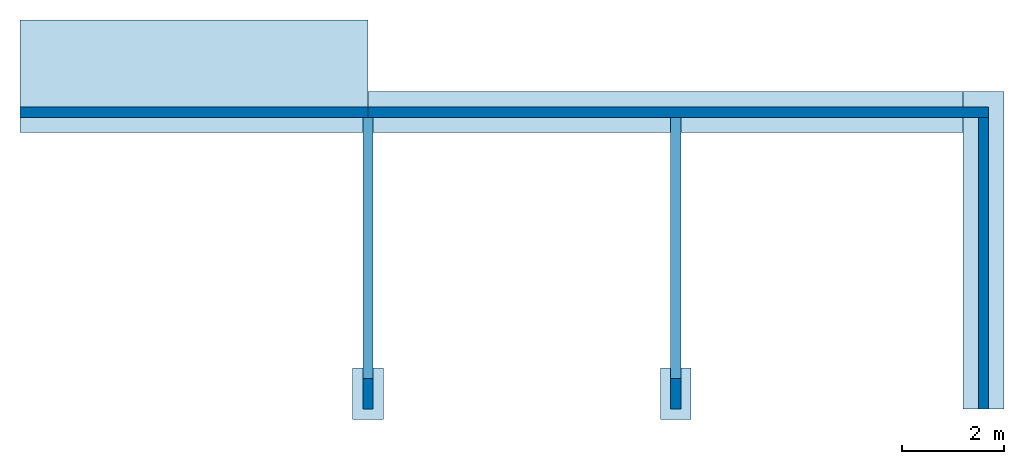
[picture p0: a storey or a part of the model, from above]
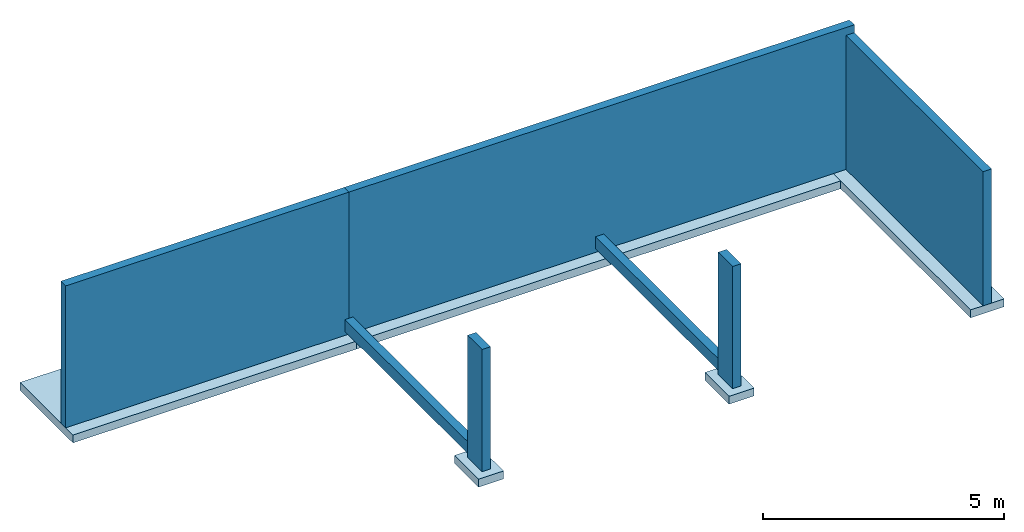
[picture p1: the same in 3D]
Properties of the parts of a building model (IFC2X3)

# File
Description: ViewDefinition [CoordinationView]
File name: Numéro du projet
Time: 2015-11-24T11:05:04
Written by: The EXPRESS Data Manager Version 5.02.0100.07 : 28 Aug 2013
Made in: 20140606_1530(x64) - Exporter 2015.0.2014.0606 - Default UI
Comment: STEP Physical File produced by: The EXPRESS Data Manager Version 5.02.0100.07 : 28 Aug 2013 * Module: EDMstepFileFactory/EDMstandAlone * Creation date: Tue Nov 24 11:05:04 2015 * Host: NI * Database: C:\Users\nicolas\AppData\Local\Temp\{986D8185-EDF2-4D71-8F7C-B6AD133C0408}\ifc * Database version: 5507 * Database creation date: Tue Nov 24 11:04:53 2015 * Schema: IFC2X3 * Model: DataRepository.ifc * Model creation date: Tue Nov 24 11:04:53 2015 * Header model: DataRepository.ifc_HeaderModel * Header model creation date: Tue Nov 24 11:04:53 2015 * EDMuser: sdai-user * EDMgroup: sdai-group * License ID and type: 5605 : Permanent license. Expiry date: * EDMstepFileFactory options: 020000

# IfcProject, Numéro du projet
LongName: Nom du projet; Phase: Etat du projet

# IfcSite, Default
RefLatitude: 48, 51, 23, 999633; RefLongitude: 2, 21, 3, 553905; RefElevation: 0 m
Autre - Adresse du projet: Entrer l'adresse ici; Catégorie: Informations sur le projet; Date de fin du projet: Date de fin; Etat du projet: Etat du projet; Nom du client: Propriétaire; Nom du projet: Nom du projet; Numéro de projet: Numéro du projet

# IfcBuilding
Pset_BuildingCommon - NumberOfStoreys: 3
Autre - Catégorie: Informations sur le projet; Adresse du projet: Entrer l'adresse ici; Date de fin du projet: Date de fin; Etat du projet: Etat du projet; Nom du client: Propriétaire; Nom du projet: Nom du projet; Numéro de projet: Numéro du projet

# IfcBuildingStorey (3)
Autre - Catégorie: Niveaux; Famille: Niveau: Ligne du Niveau; Famille et type: Niveau: Ligne du Niveau; ID du type: Niveau: Ligne du Niveau; Type: Niveau: Ligne du Niveau; Nom de la famille: Niveau
Cotes - Hauteur de calcul: 0 m
Données d'identification - Etage de bâtiment: yes; Structure: no; Nom du type: Ligne du Niveau
Contraintes - Base de l'élévation: Point de base du projet
Graphismes - Couleur: 12632256; Epaisseur des lignes: 1; Motif des lignes: Tiret point; Symbole: Marqueur de niveau - Point triangulaire: Marqueur de niveau - Point triangulaire; Valeur par défaut du symbole à l'extrémité 1: no; Valeur par défaut du symbole à l'extrémité 2: yes
Name | LongName = Nom | Elevation (m) = Elévation (m)
4 - Fondations | 4 - Fondations | -0.6
3 - Sous sol | 3 - Sous sol | 0
2 - RdC | 2 - RdC | 3

# IfcFooting: Base rectangulaire:100 x 60 x 25 (2)
In: 4 - Fondations
Material: Béton - Béton coulé sur place
Autre - Catégorie: Fondations; Famille: Base rectangulaire: 100 x 60 x 25; Famille et type: Base rectangulaire: 100 x 60 x 25; ID du type: Base rectangulaire: 100 x 60 x 25; Type: Base rectangulaire: 100 x 60 x 25; Nom de la famille: Base rectangulaire
Contraintes - Décalage: 0 m; Hôte: Niveau : 4 - Fondations; Niveau: Niveau: 4 - Fondations; Se déplace avec les quadrillages: yes
Cotes - Elévation à la base: -0.8 m; Elévation en haut: -0.6 m; Largeur: 0.6 m; Longueur: 1 m; Surface: 1.84 m2; Volume: 0.24 m3; Epaisseur: 0.2 m
Matériaux et finitions - Matériau structurel: Béton - Béton coulé sur place
Phase de construction - Phase de création: Nouvelle construction
Structure - Activer le modèle analytique: yes; Enrobage d'armature - Autres faces: Paramètres de l'enrobage d'armature: Enrobage d'armature 1; Enrobage d'armature - Face inférieure: Paramètres de l'enrobage d'armature: Enrobage d'armature 1; Enrobage d'armature - Face supérieure: Paramètres de l'enrobage d'armature: Enrobage d'armature 1
Données d'identification - Nom du type: 100 x 60 x 25
Name (Base rectangulaire:100 x 60 x 25:...)
241491
241772

# IfcFooting: Semelle filante:0.6 x 0.2 (2)
In: 4 - Fondations
PredefinedType: STRIP_FOOTING; Material: Maçonnerie - Béton
Autre - Catégorie: Fondations; Famille: Semelle filante: 0.6 x 0.2; Famille et type: Semelle filante: 0.6 x 0.2; ID du type: Semelle filante: 0.6 x 0.2; Type: Semelle filante: 0.6 x 0.2; Nom de la famille: Semelle filante
Cotes - Elévation à la base: -0.8 m; Elévation en haut: -0.6 m; Largeur: 0.8 m; Epaisseur de fondation: 0.2 m; Largeur côté extérieur: 0.3 m; Largeur côté intérieur: 0.3 m; Longueur de l'extension de fin par défaut: 0 m; Ne pas couper aux insertions: no
Phase de construction - Phase de création: Nouvelle construction
Structure - Activer le modèle analytique: yes; Enrobage d'armature - Autres faces: Paramètres de l'enrobage d'armature: Enrobage d'armature 1; Enrobage d'armature - Face inférieure: Paramètres de l'enrobage d'armature: Enrobage d'armature 1; Enrobage d'armature - Face supérieure: Paramètres de l'enrobage d'armature: Enrobage d'armature 1; Utilisation structurelle: Soutènement
Données d'identification - Nom du type: 0.6 x 0.2
Matériaux et finitions - Matériau structurel: Maçonnerie - Béton
Name (Semelle filante:0.6 x 0.2:...) | Longueur (m) | Volume (m3)
242070 | 5.7 | 0.992
247916 | 12.12 | 1.8592

# IfcFooting: Semelle filante:cantil 2 x 0.2, Semelle filante:cantil 2 x 0.2:242081
In: 4 - Fondations
PredefinedType: STRIP_FOOTING; Material: Maçonnerie - Béton
Autre - Catégorie: Fondations; Famille: Semelle filante: cantil 2 x 0.2; Famille et type: Semelle filante: cantil 2 x 0.2; ID du type: Semelle filante: cantil 2 x 0.2; Type: Semelle filante: cantil 2 x 0.2; Nom de la famille: Semelle filante
Cotes - Elévation à la base: -0.8 m; Elévation en haut: -0.6 m; Largeur: 2.2 m; Longueur: 6.79606 m; Volume: 2.99027 m3; Longueur de l'extension de fin par défaut: 0 m; Ne pas couper aux insertions: no; Epaisseur de fondation: 0.2 m; Largeur côté extérieur: 1.7 m; Largeur côté intérieur: 0.3 m
Phase de construction - Phase de création: Nouvelle construction
Structure - Activer le modèle analytique: yes; Enrobage d'armature - Autres faces: Paramètres de l'enrobage d'armature: Enrobage d'armature 1; Enrobage d'armature - Face inférieure: Paramètres de l'enrobage d'armature: Enrobage d'armature 1; Enrobage d'armature - Face supérieure: Paramètres de l'enrobage d'armature: Enrobage d'armature 1; Utilisation structurelle: Soutènement
Données d'identification - Nom du type: cantil 2 x 0.2
Matériaux et finitions - Matériau structurel: Maçonnerie - Béton

# IfcSlab: Sol:Dalle en béton - 200 mm (2)
PredefinedType: FLOOR; Material: Maçonnerie - Béton 0.2 m
Pset_SlabCommon - LoadBearing: yes; Reference: Dalle en béton - 200 mm; IsExternal: no; PitchAngle: 0 deg
Autre - Catégorie: Sols; Famille: Sol: Dalle en béton - 200 mm; Famille et type: Sol: Dalle en béton - 200 mm; ID du type: Sol: Dalle en béton - 200 mm; Type: Sol: Dalle en béton - 200 mm; Nom de la famille: Sol
Contraintes - Lié au volume: no; Limite de pièce: yes; Décalage par rapport au niveau: 0 m
Cotes - Epaisseur: 0.2 m
Phase de construction - Phase de création: Nouvelle construction
Structure - Activer le modèle analytique: yes; Enrobage d'armature - Autres faces: Paramètres de l'enrobage d'armature: Enrobage d'armature 1; Structure: yes; Enrobage d'armature - Face inférieure: Paramètres de l'enrobage d'armature: Enrobage d'armature 1; Enrobage d'armature - Face supérieure: Paramètres de l'enrobage d'armature: Enrobage d'armature 1
Construction - Epaisseur par défaut: 0.2 m; Fonction: Intérieur
Données d'identification - Nom du type: Dalle en béton - 200 mm
Graphismes - Couleur vue détail faible: 0
Matériaux et finitions - Matériau structurel: Maçonnerie - Béton
Propriétés analytiques - Rugosité: 3; Coefficient d'absorbance: 0.7
Name (Sol:Dalle en béton - 200 mm:...) | In | Niveau | Périmètre (m) | Surface (m2) | Volume (m3)
237324 | 3 - Sous sol | Niveau: 3 - Sous sol | 36.64 | 68.274 | 13.6548
238114 | 2 - RdC | Niveau: 2 - RdC | 39.84 | 78.426 | 15.6852

# IfcStair: Escalier coulé sur place:Monobloc:189391, Escalier coulé sur place:Escalier:244176
In: 3 - Sous sol
Pset_StairCommon - IsExternal: no; Reference: Monobloc; NumberOfRiser: 16; NumberOfTreads: 15; RiserHeight: 0.1875 m; TreadLength: 0.255 m
Autre - Catégorie: Escalier; Famille: Escalier coulé sur place: Monobloc; Famille et type: Escalier coulé sur place: Monobloc; ID du type: Escalier coulé sur place: Monobloc; Type: Escalier coulé sur place: Monobloc; Nom de la famille: Escalier coulé sur place
Contraintes - Décalage inférieur: 0 m; Décalage supérieur: 0 m; Hauteur d'escalier souhaitée: 3 m; Niveau de base: Niveau: 3 - Sous sol; Niveau supérieur: Niveau: 2 - RdC
Cotes - Hauteur actuelle de la contremarche: 0.1875 m; Nombre de contremarches souhaité: 16; Nombre réel de contremarches: 16; Numéro initial de marche/contremarche: 1; Profondeur actuelle du giron: 0.255 m
Phase de construction - Phase de création: Nouvelle construction
Structure - Enrobage d'armature: Paramètres de l'enrobage d'armature: Enrobage d'armature 1
Construction - Fonction: Intérieur; Type de palier: Palier monobloc: Epaisseur 150 mm; Type de volée: Volée monobloc: Profondeur de structure 80 mm
Données d'identification - Nom du type: Monobloc
Graphismes - Type de symbole de coupe: Symbole de coupure d'escalier: Zigzag simple
Règles de calcul - Hauteur maximum de la contremarche: 0.19 m; Largeur de volée minimale: 1 m; Profondeur de marche minimale: 0.23 m
Supports - Décalage latéral droit: 0 m; Décalage latéral gauche: 0 m; Nombre de supports intermédiaires: 0; Support droit: Aucun; Support gauche: Aucun; Support intermédiaire: no

# IfcStairFlight: Escalier coulé sur place:Monobloc:189391, Escalier coulé sur place:Escalier:244176 Run 1
In: 3 - Sous sol
NumberOfRiser: 16; NumberOfTreads: 15; RiserHeight: 0.615157 m; TreadLength: 0.836614 m; Material: Maçonnerie - Béton
Pset_StairFlightCommon - Reference: Profondeur de structure 80 mm; NumberOfRiser: 16; NumberOfTreads: 15; RiserHeight: 0.1875 m; TreadLength: 0.255 m; TreadLengthAtOffset: 0.255 m; NosingLength: 0 m; WalkingLineOffset: 0.6 m; WaistThickness: 1.2 m
Autre - Catégorie: Volées; Famille: Volée monobloc: Profondeur de structure 80 mm; Famille et type: Volée monobloc: Profondeur de structure 80 mm; ID du type: Volée monobloc: Profondeur de structure 80 mm; Type: Volée monobloc: Profondeur de structure 80 mm; Nom de la famille: Volée monobloc
Construction - Débuter avec contremarche: yes; Etendre la base de contremarche inférieure: 0 m; Finir avec contremarche: yes; Paillasse: Lissée; Profondeur structurelle: 0.08 m
Contraintes - Hauteur de base relative: 0 m; Hauteur de la volée: 3 m; Hauteur maximale relative: 3 m; Ligne de justification: Volée: gauche
Cotes - Hauteur réelle des contremarches: 0.1875 m; Largeur réelle de la volée: 1.2 m; Nombre réel de contremarches: 16; Nombre réel de marches: 15; Profondeur réelle des marches: 0.255 m
Phase de construction - Phase de création: Nouvelle construction
Contremarches - Connexion contremarche à marche: Marche dessous la contremarche; Contremarche: no; Epaisseur de la contremarche: 0 m; Inclinée: no
Données d'identification - Nom du type: Profondeur de structure 80 mm
Marches - Appliquer un nez de marche: Devant seulement; Epaisseur de la marche: 0 m; Longueur du nez de marche: 0 m; Marche: no
Matériaux et finitions - Matériau monobloc: Maçonnerie - Béton

# IfcWallStandardCase: Mur de base:Générique - Ext. 200 mm (13)
Type - PredefinedType: STANDARD; Material: Mur par défaut 0.2 m
Type - Autre - Catégorie: Murs; Nom de la famille: Mur de base
Type - Construction - Fonction: Extérieur; Largeur: 0.2 m; Retournement aux extrémités: Aucun(e); Retournement aux insertions: Ne pas retourner
Type - Données d'identification - Nom du type: Générique - Ext. 200 mm
Type - Graphismes - Couleur vue détail faible: 0
Type - Matériaux et finitions - Matériau structurel: Mur par défaut
Type - Propriétés analytiques - Coefficient d'absorbance: 0.7; Rugosité: 3
Autre - Famille: Mur de base: Générique - Ext. 200 mm; Famille et type: Mur de base: Générique - Ext. 200 mm; ID du type: Mur de base: Générique - Ext. 200 mm; Type: Mur de base: Générique - Ext. 200 mm
Contraintes - Extension inférieure: 0 m; Extension supérieure: 0 m; Lié au volume: no; Limite de pièce: yes; Partie inférieure attachée: no
Phase de construction - Phase de création: Nouvelle construction
Structure - Activer le modèle analytique: yes; Enrobage d'armature - Autres faces: Paramètres de l'enrobage d'armature: Enrobage d'armature 1; Enrobage d'armature - Face extérieure: Paramètres de l'enrobage d'armature: Enrobage d'armature 1; Enrobage d'armature - Face intérieure: Paramètres de l'enrobage d'armature: Enrobage d'armature 1; Structure: yes; Utilisation structurelle: Porteur
Pset_WallCommon - Reference: Générique - Ext. 200 mm; LoadBearing: yes; IsExternal: yes
Name (Mur de base:Générique - Ext. 200 mm:...) | In | Contrainte inférieure | Contrainte supérieure | Décalage inférieur (m) | Décalage supérieur (m) | Hauteur non contrainte (m) | Ligne de justification | Partie supérieure attachée = ExtendToStructure | Longueur (m) | Surface (m2) | Volume (m3)
235339 | 4 - Fondations | Niveau: 4 - Fondations | Niveau: 1 - Arase sup GC | 0 | -0.9 | 3.6 | Axe du mur | no | 6.79606 | 24.4658 | 4.89316
236229 | 4 - Fondations | Niveau: 4 - Fondations | Niveau: 2 - RdC | 0 | 0 | 3.6 | Nu fini: Extérieur | yes | 5.8 | 19.38 | 3.876
236689 | 4 - Fondations | Niveau: 4 - Fondations | Niveau: 2 - RdC | 0 | -0.5 | 3.1 | Axe du mur | no | 0.6 | 1.86 | 0.372
236878 | 4 - Fondations | Niveau: 4 - Fondations | Niveau: 2 - RdC | 0 | -0.5 | 3.1 | Axe du mur | no | 0.6 | 1.86 | 0.372
239348 | 2 - RdC | Niveau: 2 - RdC | Niveau: 1 - Arase sup GC | 0 | 0 | 0.9 | Nu fini: Intérieur | no | 6.4 | 5.85 | 1.17
239495 | 2 - RdC | Niveau: 2 - RdC | Niveau: 1 - Arase sup GC | 0 | 0 | 0.9 | Nu fini: Extérieur | no | 12.02 | 10.818 | 2.1636
239718 | 2 - RdC | Niveau: 2 - RdC | Niveau: 1 - Arase sup GC | 0 | 0 | 0.9 | Nu fini: Extérieur | no | 5.2 | 4.59 | 0.918
242637 | 4 - Fondations | Niveau: 4 - Fondations | Niveau: 3 - Sous sol | 0.1 | -0.2 | 0.3 | Nu fini: Intérieur | no | 5.2 | 1.53 | 0.306
242943 | 4 - Fondations | Niveau: 4 - Fondations | Niveau: 3 - Sous sol | 0.1 | -0.2 | 0.3 | Nu fini: Intérieur | no | 5.2 | 1.53 | 0.306
245680 | 3 - Sous sol | Niveau: 3 - Sous sol | Niveau: 2 - RdC | 2.5 | -0.2 | 0.3 | Nu fini: Intérieur | yes | 6.4 | 1.89 | 0.378
245949 | 3 - Sous sol | Niveau: 3 - Sous sol | Niveau: 2 - RdC | 2.5 | -0.2 | 0.3 | Nu fini: Intérieur | yes | 6.4 | 1.89 | 0.378
246354 | 3 - Sous sol | Niveau: 3 - Sous sol | Niveau: 2 - RdC | 2.5 | 0 | 0.5 | Nu fini: Intérieur | yes | 0.6 | 0.18 | 0.036
247914 | 4 - Fondations | Niveau: 4 - Fondations | Niveau: 1 - Arase sup GC | 0 | -0.9 | 3.6 | Axe du mur | no | 12.02 | 43.632 | 8.7264
